One B-rep face of a CAD part: STEP entity #338.
In plain terms, the planar face has unit normal (0, 0, 1).
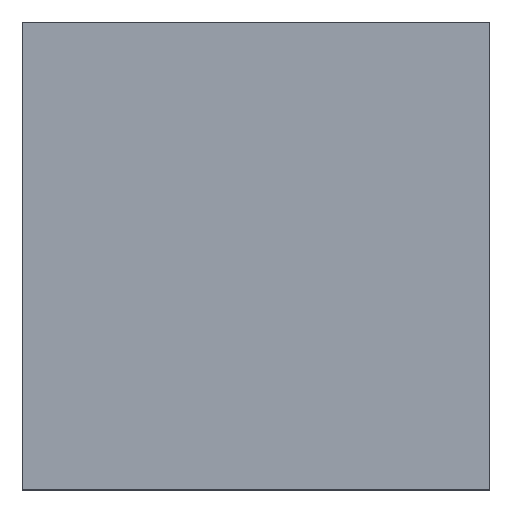
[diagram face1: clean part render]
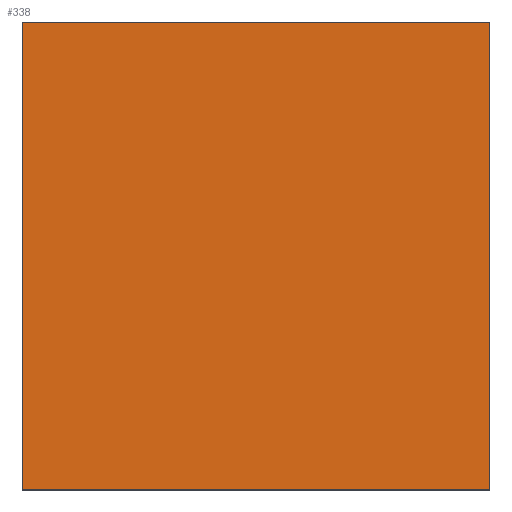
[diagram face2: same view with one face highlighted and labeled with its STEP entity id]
Its self-contained STEP definition (entity closure, numbers rounded to 3 decimals):
#21 = EDGE_CURVE('',#22,#24,#26,.T.);
#22 = VERTEX_POINT('',#23);
#23 = CARTESIAN_POINT('',(-35.,107.,48.));
#24 = VERTEX_POINT('',#25);
#25 = CARTESIAN_POINT('',(-35.,87.,48.));
#26 = SURFACE_CURVE('',#27,(#31,#43),.PCURVE_S1.);
#27 = LINE('',#28,#29);
#28 = CARTESIAN_POINT('',(-35.,87.,48.));
#29 = VECTOR('',#30,1.);
#30 = DIRECTION('',(0.,-1.,0.));
#31 = PCURVE('',#32,#37);
#32 = PLANE('',#33);
#33 = AXIS2_PLACEMENT_3D('',#34,#35,#36);
#34 = CARTESIAN_POINT('',(-35.,87.,38.));
#35 = DIRECTION('',(1.,0.,0.));
#36 = DIRECTION('',(0.,0.,1.));
#37 = DEFINITIONAL_REPRESENTATION('',(#38),#42);
#38 = LINE('',#39,#40);
#39 = CARTESIAN_POINT('',(10.,0.));
#40 = VECTOR('',#41,1.);
#41 = DIRECTION('',(0.,1.));
#42 = ( GEOMETRIC_REPRESENTATION_CONTEXT(2) 
PARAMETRIC_REPRESENTATION_CONTEXT() REPRESENTATION_CONTEXT('2D SPACE',''
  ) );
#43 = PCURVE('',#44,#49);
#44 = PLANE('',#45);
#45 = AXIS2_PLACEMENT_3D('',#46,#47,#48);
#46 = CARTESIAN_POINT('',(-35.,87.,48.));
#47 = DIRECTION('',(0.,0.,1.));
#48 = DIRECTION('',(1.,0.,0.));
#49 = DEFINITIONAL_REPRESENTATION('',(#50),#54);
#50 = LINE('',#51,#52);
#51 = CARTESIAN_POINT('',(0.,0.));
#52 = VECTOR('',#53,1.);
#53 = DIRECTION('',(0.,-1.));
#54 = ( GEOMETRIC_REPRESENTATION_CONTEXT(2) 
PARAMETRIC_REPRESENTATION_CONTEXT() REPRESENTATION_CONTEXT('2D SPACE',''
  ) );
#72 = PLANE('',#73);
#73 = AXIS2_PLACEMENT_3D('',#74,#75,#76);
#74 = CARTESIAN_POINT('',(-35.,107.,38.));
#75 = DIRECTION('',(0.,1.,0.));
#76 = DIRECTION('',(0.,0.,1.));
#126 = PLANE('',#127);
#127 = AXIS2_PLACEMENT_3D('',#128,#129,#130);
#128 = CARTESIAN_POINT('',(-35.,87.,38.));
#129 = DIRECTION('',(0.,1.,0.));
#130 = DIRECTION('',(0.,0.,1.));
#144 = VERTEX_POINT('',#145);
#145 = CARTESIAN_POINT('',(-15.,87.,48.));
#152 = PLANE('',#153);
#153 = AXIS2_PLACEMENT_3D('',#154,#155,#156);
#154 = CARTESIAN_POINT('',(-15.,87.,38.));
#155 = DIRECTION('',(1.,0.,0.));
#156 = DIRECTION('',(0.,0.,1.));
#195 = VERTEX_POINT('',#196);
#196 = CARTESIAN_POINT('',(-15.,107.,48.));
#217 = EDGE_CURVE('',#144,#195,#218,.T.);
#218 = SURFACE_CURVE('',#219,(#223,#230),.PCURVE_S1.);
#219 = LINE('',#220,#221);
#220 = CARTESIAN_POINT('',(-15.,87.,48.));
#221 = VECTOR('',#222,1.);
#222 = DIRECTION('',(0.,1.,0.));
#223 = PCURVE('',#152,#224);
#224 = DEFINITIONAL_REPRESENTATION('',(#225),#229);
#225 = LINE('',#226,#227);
#226 = CARTESIAN_POINT('',(10.,0.));
#227 = VECTOR('',#228,1.);
#228 = DIRECTION('',(0.,-1.));
#229 = ( GEOMETRIC_REPRESENTATION_CONTEXT(2) 
PARAMETRIC_REPRESENTATION_CONTEXT() REPRESENTATION_CONTEXT('2D SPACE',''
  ) );
#230 = PCURVE('',#44,#231);
#231 = DEFINITIONAL_REPRESENTATION('',(#232),#236);
#232 = LINE('',#233,#234);
#233 = CARTESIAN_POINT('',(20.,0.));
#234 = VECTOR('',#235,1.);
#235 = DIRECTION('',(0.,1.));
#236 = ( GEOMETRIC_REPRESENTATION_CONTEXT(2) 
PARAMETRIC_REPRESENTATION_CONTEXT() REPRESENTATION_CONTEXT('2D SPACE',''
  ) );
#242 = EDGE_CURVE('',#24,#144,#243,.T.);
#243 = SURFACE_CURVE('',#244,(#248,#255),.PCURVE_S1.);
#244 = LINE('',#245,#246);
#245 = CARTESIAN_POINT('',(-35.,87.,48.));
#246 = VECTOR('',#247,1.);
#247 = DIRECTION('',(1.,0.,0.));
#248 = PCURVE('',#126,#249);
#249 = DEFINITIONAL_REPRESENTATION('',(#250),#254);
#250 = LINE('',#251,#252);
#251 = CARTESIAN_POINT('',(10.,0.));
#252 = VECTOR('',#253,1.);
#253 = DIRECTION('',(0.,1.));
#254 = ( GEOMETRIC_REPRESENTATION_CONTEXT(2) 
PARAMETRIC_REPRESENTATION_CONTEXT() REPRESENTATION_CONTEXT('2D SPACE',''
  ) );
#255 = PCURVE('',#44,#256);
#256 = DEFINITIONAL_REPRESENTATION('',(#257),#261);
#257 = LINE('',#258,#259);
#258 = CARTESIAN_POINT('',(0.,0.));
#259 = VECTOR('',#260,1.);
#260 = DIRECTION('',(1.,0.));
#261 = ( GEOMETRIC_REPRESENTATION_CONTEXT(2) 
PARAMETRIC_REPRESENTATION_CONTEXT() REPRESENTATION_CONTEXT('2D SPACE',''
  ) );
#310 = EDGE_CURVE('',#22,#195,#311,.T.);
#311 = SURFACE_CURVE('',#312,(#316,#323),.PCURVE_S1.);
#312 = LINE('',#313,#314);
#313 = CARTESIAN_POINT('',(-35.,107.,48.));
#314 = VECTOR('',#315,1.);
#315 = DIRECTION('',(1.,0.,0.));
#316 = PCURVE('',#72,#317);
#317 = DEFINITIONAL_REPRESENTATION('',(#318),#322);
#318 = LINE('',#319,#320);
#319 = CARTESIAN_POINT('',(10.,0.));
#320 = VECTOR('',#321,1.);
#321 = DIRECTION('',(0.,1.));
#322 = ( GEOMETRIC_REPRESENTATION_CONTEXT(2) 
PARAMETRIC_REPRESENTATION_CONTEXT() REPRESENTATION_CONTEXT('2D SPACE',''
  ) );
#323 = PCURVE('',#44,#324);
#324 = DEFINITIONAL_REPRESENTATION('',(#325),#329);
#325 = LINE('',#326,#327);
#326 = CARTESIAN_POINT('',(0.,20.));
#327 = VECTOR('',#328,1.);
#328 = DIRECTION('',(1.,0.));
#329 = ( GEOMETRIC_REPRESENTATION_CONTEXT(2) 
PARAMETRIC_REPRESENTATION_CONTEXT() REPRESENTATION_CONTEXT('2D SPACE',''
  ) );
#338 = ADVANCED_FACE('',(#339),#44,.T.);
#339 = FACE_BOUND('',#340,.T.);
#340 = EDGE_LOOP('',(#341,#342,#343,#344));
#341 = ORIENTED_EDGE('',*,*,#21,.T.);
#342 = ORIENTED_EDGE('',*,*,#242,.T.);
#343 = ORIENTED_EDGE('',*,*,#217,.T.);
#344 = ORIENTED_EDGE('',*,*,#310,.F.);
